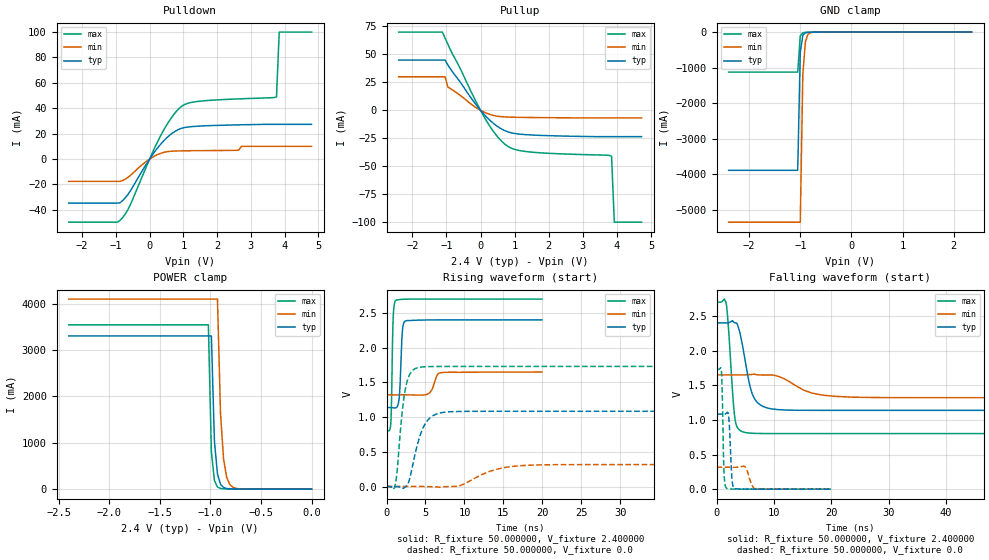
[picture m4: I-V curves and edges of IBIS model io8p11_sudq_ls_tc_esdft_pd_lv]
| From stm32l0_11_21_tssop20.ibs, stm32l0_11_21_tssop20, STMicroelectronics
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|   Model io8p11_sudq_ls_tc_esdft_pd_lv
[Model]  io8p11_sudq_ls_tc_esdft_pd_lv
Model_type I/O
Polarity   Non-Inverting
Enable   Active-Low
Vinl =   0.720000V
Vinh =   1.680000V
Vmeas =  1.200000V
Cref =   50.000000pF
Rref =   100.000000M
Vref =   0.0V
C_comp   2.242700pF   2.201100pF   2.288600pF
[Temperature Range]   25.000000   0.105000k   -40.000000
[Pullup Reference]   2.400000V   1.650000V   2.700000V
[Pulldown Reference]   0.0V   0.0V   0.0V
[POWER Clamp Reference]   2.400000V   1.650000V   2.700000V
[GND Clamp Reference]   0.0V   0.0V   0.0V
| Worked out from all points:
|   slope of the pulldown table from 0 to 0.36 V, typ, clamps not added: 28.4 ohm
|   slope of the pullup table from 0 to 0.36 V, typ, clamps not added: 32.2 ohm
|   GND clamp passes 1 mA (typ) near -0.64 V on its own axis
|   POWER clamp passes 1 mA (typ) near -0.63 V on its own axis
|   rising waveform, R_fixture 50.000000, V_fixture 2.400000: 20-80 % time 282ps typ, 638ps min, 189ps max; typ from 1.14 V to 2.4 V
|   rising waveform, R_fixture 50.000000, V_fixture 0.0: 20-80 % time 1.6ns typ, 3.9ns min, 928ps max; typ from 0 V to 1.08 V
|   falling waveform, R_fixture 50.000000, V_fixture 2.400000: 20-80 % time 1.8ns typ, 4.73ns min, 909ps max; typ from 2.4 V to 1.14 V
|   falling waveform, R_fixture 50.000000, V_fixture 0.0: 20-80 % time 358ps typ, 768ps min, 265ps max; typ from 1.08 V to 0 V
[Pulldown]
|Voltage   I(typ)   I(min)   I(max)
-2.4V     -34.71mA   -17.61mA   -49.77mA
-880mV    -34.55mA   -17.61mA   -48.41mA
-560mV    -24.66mA   -12.69mA   -35.31mA
240mV     8.893mA    3.542mA    13.9mA
560mV     17.98mA    5.931mA    29.16mA
880mV     23.58mA    6.389mA    40.03mA
1.44V     25.89mA    6.593mA    45.41mA
2.64V     26.92mA    7mA        47.38mA
2.72V     26.96mA    10mA       47.46mA
3.76V     27.3mA     10mA       49mA
3.84V     27.3mA     10mA       100mA
4.8V      27.3mA     10mA       100mA
[Pullup]
|Voltage   I(typ)   I(min)   I(max)
-2.4V     45mA       30mA       70mA
-1.12V    45mA       30mA       70mA
-1.04V    45mA       30mA       64.7mA
-960mV    40.7mA     21mA       59.3mA
80mV      -2.838mA   -1.261mA   -4.478mA
480mV     -14.04mA   -5.167mA   -22.91mA
800mV     -19.21mA   -5.978mA   -32.18mA
1.04V     -20.85mA   -6.184mA   -35.23mA
1.44V     -21.93mA   -6.373mA   -37.19mA
3.84V     -23.5mA    -6.7mA     -41mA
3.92V     -23.5mA    -6.7mA     -100mA
4.72V     -23.5mA    -6.7mA     -100mA
[GND_clamp]
|Voltage   I(typ)   I(min)   I(max)
-2.4V     -3.892A    -5.353A    -1.127A
-1.05V    -3.892A    -5.353A    -1.127A
-1V       -568.8mA   -5.353A    -105.4mA
-950mV    -88.96mA   -1.19A     -18.04mA
-900mV    -18.16mA   -269.2mA   -8.968mA
-850mV    -6.712mA   -63.46mA   -6.577mA
-800mV    -4.026mA   -16.62mA   -4.866mA
-650mV    -1.055mA   -1.234mA   -1.154mA
2.35V     53.38uA    50.3uA     37.53uA
[POWER_clamp]
|Voltage   I(typ)   I(min)   I(max)
-2.4V     3.303A     4.097A     3.542A
-1.02V    3.303A     4.097A     3.542A
-990mV    3.303A     4.097A     802.4mA
-960mV    1.032A     4.097A     186.5mA
-930mV    325.2mA    4.097A     47.59mA
-900mV    104.8mA    1.637A     15.78mA
-870mV    35.83mA    655.7mA    8.015mA
-840mV    13.93mA    263.9mA    5.668mA
-810mV    6.712mA    107.2mA    4.56mA
-780mV    4.088mA    44.39mA    3.763mA
-690mV    1.741mA    4.361mA    1.91mA
0V        0A         0A         0A
[Ramp]
| variable   typ   min   max
dV/dt_r  0.65004/1.59528n   0.18967/3.89323n   1.03746/0.92560n
dV/dt_f  0.75702/1.80144n   0.19728/4.72445n   1.13766/0.90706n
R_load = 50.000000
[Rising Waveform]
R_fixture= 50.000000
V_fixture= 2.400000
V_fixture_min= 1.650000
V_fixture_max= 2.700000
|time   V(typ)   V(min)   V(max)
0s        1.137V     1.32V      802.2mV
560.6ps   1.137V     1.32V      929mV
840.8ps   1.133V     1.32V      2.392V
1.201ns   1.133V     1.32V      2.682V
1.602ns   1.254V     1.32V      2.692V
2.042ns   2.246V     1.32V      2.696V
2.442ns   2.385V     1.32V      2.697V
5.405ns   2.398V     1.34V      2.699V
7.047ns   2.399V     1.64V      2.699V
19.94ns   2.399V     1.649V     2.699V
[Rising Waveform]
R_fixture= 50.000000
V_fixture= 0.0
V_fixture_min= 0.0
V_fixture_max= 0.0
|time   V(typ)   V(min)   V(max)
0s        1.003uV    6.542uV    233.6uV
1.126ns   -47.93uV   1.825uV    29.53mV
2.002ns   -17.57mV   -5.005uV   1.066V
2.377ns   -9.593mV   13.27uV    1.38V
3.003ns   125.8mV    75.34uV    1.622V
4.004ns   621.6mV    83.25uV    1.711V
5.506ns   981mV      -1.71mV    1.727V
8.258ns   1.078V     -331.5uV   1.729V
17.14ns   1.083V     299.9mV    1.729V
62.31ns   1.083V     316.1mV    1.729V
[Falling Waveform]
R_fixture= 50.000000
V_fixture= 2.400000
V_fixture_min= 1.650000
V_fixture_max= 2.700000
|time   V(typ)   V(min)   V(max)
0s        2.399V     1.649V     2.699V
1.627ns   2.399V     1.649V     2.704V
2.002ns   2.4V       1.649V     2.418V
3.128ns   2.403V     1.649V     1.07V
3.504ns   2.397V     1.649V     911.9mV
4.505ns   2.084V     1.648V     829.6mV
6.381ns   1.344V     1.658V     806.1mV
9.635ns   1.158V     1.647V     802.5mV
20.9ns    1.137V     1.338V     802.2mV
62.31ns   1.137V     1.32V      802.2mV
[Falling Waveform]
R_fixture= 50.000000
V_fixture= 0.0
V_fixture_min= 0.0
V_fixture_max= 0.0
|time   V(typ)   V(min)   V(max)
0s        1.083V     316.1mV    1.729V
840.8ps   1.083V     316.1mV    1.711V
1.001ns   1.083V     316.1mV    1.365V
1.281ns   1.083V     316.1mV    290.7mV
1.722ns   1.097V     316.1mV    16.64mV
2.122ns   1.046V     316.1mV    3.571mV
2.683ns   151.8mV    315.9mV    1.944mV
3.123ns   11.17mV    315.7mV    1.456mV
6.727ns   577.6uV    7.144mV    275.5uV
19.94ns   1.003uV    6.542uV    233.6uV
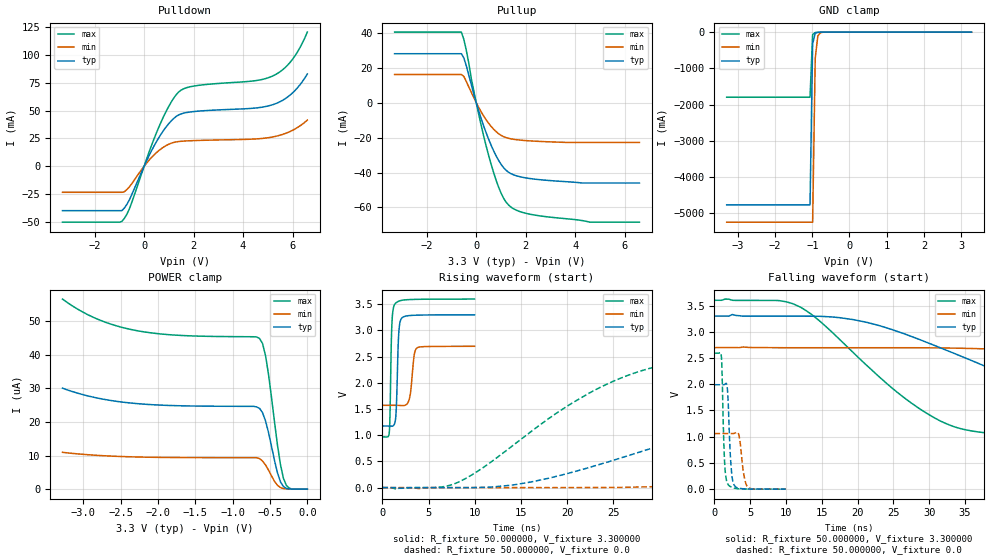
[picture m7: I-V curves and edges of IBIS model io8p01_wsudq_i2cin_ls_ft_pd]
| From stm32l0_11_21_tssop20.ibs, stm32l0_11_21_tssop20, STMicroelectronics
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|   Model io8p01_wsudq_i2cin_ls_ft_pd
[Model]  io8p01_wsudq_i2cin_ls_ft_pd
Model_type I/O
Polarity   Non-Inverting
Enable   Active-Low
Vinl =   0.990000V
Vinh =   2.310000V
Vmeas =  1.650000V
Cref =   50.000000pF
Rref =   100.000000M
Vref =   0.0V
C_comp   3.020400pF   2.988200pF   3.054500pF
[Temperature Range]   25.000000   0.125000k   -40.000000
[Pullup Reference]   3.300000V   2.700000V   3.600000V
[Pulldown Reference]   0.0V   0.0V   0.0V
[POWER Clamp Reference]   3.300000V   2.700000V   3.600000V
[GND Clamp Reference]   0.0V   0.0V   0.0V
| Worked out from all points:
|   slope of the pulldown table from 0 to 0.495 V, typ, clamps not added: 22.6 ohm
|   slope of the pullup table from 0 to 0.495 V, typ, clamps not added: 23.9 ohm
|   GND clamp passes 1 mA (typ) near -0.64 V on its own axis
|   rising waveform, R_fixture 50.000000, V_fixture 3.300000: 20-80 % time 222ps typ, 368ps min, 182ps max; typ from 1.18 V to 3.3 V
|   rising waveform, R_fixture 50.000000, V_fixture 0.0: 20-80 % time 27.1ns typ, 59.4ns min, 13.6ns max; typ from 0 V to 1.99 V
|   falling waveform, R_fixture 50.000000, V_fixture 3.300000: 20-80 % time 24.2ns typ, 53.5ns min, 13.3ns max; typ from 3.3 V to 1.18 V
|   falling waveform, R_fixture 50.000000, V_fixture 0.0: 20-80 % time 406ps typ, 571ps min, 327ps max; typ from 1.99 V to 0 V
[Pulldown]
|Voltage   I(typ)   I(min)   I(max)
-3.3V     -39.83mA   -23.37mA   -50.2mA
-900mV    -39.83mA   -23.37mA   -49.53mA
-600mV    -30.28mA   -18.59mA   -38.45mA
500mV     22.11mA    12.28mA    30.1mA
1V        38.33mA    19.81mA    53.88mA
1.4V      46.1mA     22.18mA    66.72mA
2V        49.07mA    23.02mA    71.93mA
4.4V      52.05mA    24.38mA    76.53mA
5.2V      55.25mA    26.3mA     81.02mA
5.6V      59.18mA    28.57mA    86.57mA
6V        65.79mA    32.24mA    95.97mA
6.6V      82.83mA    41.41mA    120.4mA
[Pullup]
|Voltage   I(typ)   I(min)   I(max)
-3.3V     27.97mA    16.08mA    40.33mA
-600mV    27.97mA    16.08mA    40.33mA
-400mV    21.07mA    12.09mA    29.9mA
-200mV    10.4mA     5.948mA    13.84mA
200mV     -9.115mA   -5.294mA   -12.98mA
600mV     -24.29mA   -13.56mA   -35.12mA
1V        -35.2mA    -18.69mA   -51.62mA
1.2V      -38.62mA   -19.99mA   -56.79mA
1.4V      -40.6mA    -20.72mA   -59.71mA
2.2V      -43.48mA   -21.92mA   -63.91mA
4.6V      -46.01mA   -22.8mA    -68.41mA
6.6V      -46.01mA   -22.8mA    -68.41mA
[GND_clamp]
|Voltage   I(typ)   I(min)   I(max)
-3.3V     -4.766A    -5.244A    -1.797A
-1.06V    -4.766A    -5.244A    -1.797A
-990mV    -326.6mA   -5.244A    -67.91mA
-920mV    -28.93mA   -722.1mA   -10.97mA
-850mV    -6.625mA   -104.2mA   -6.541mA
-780mV    -3.477mA   -17.29mA   -4.218mA
-500mV    -68.5uA    -183uA     -41.48uA
3.28V     73.94uA    88.61uA    51.47uA
[POWER_clamp]
|Voltage   I(typ)   I(min)   I(max)
-3.28V    30.07uA    10.97uA    56.59uA
-2.84V    27.25uA    10.1uA     50.89uA
-2.32V    25.55uA    9.602uA    47.34uA
-640mV    24.06uA    9.099uA    44.84uA
-600mV    22.76uA    8.364uA    43.37uA
-560mV    20.32uA    7.211uA    39.74uA
-520mV    16.86uA    5.675uA    34.14uA
-400mV    4.841uA    1.145uA    13.1uA
-360mV    2.184uA    477.2nA    7.288uA
-320mV    772.4nA    180.3nA    3.213uA
-240mV    60.03nA    0A         295.3nA
0V        0A         0A         0A
[Ramp]
| variable   typ   min   max
dV/dt_r  1.19406/27.03659n   0.63468/59.45171n   1.55520/13.56326n
dV/dt_f  1.27386/24.21250n   0.67098/53.43684n   1.57834/13.29695n
R_load = 50.000000
[Rising Waveform]
R_fixture= 50.000000
V_fixture= 3.300000
V_fixture_min= 2.700000
V_fixture_max= 3.600000
|time   V(typ)   V(min)   V(max)
0s        1.176V     1.571V     968.8mV
740.7ps   1.175V     1.571V     1.037V
1.021ns   1.172V     1.571V     3.074V
1.361ns   1.242V     1.571V     3.506V
1.522ns   1.566V     1.571V     3.534V
1.782ns   2.966V     1.57V      3.559V
2.102ns   3.236V     1.566V     3.576V
2.923ns   3.284V     1.695V     3.589V
3.764ns   3.292V     2.669V     3.594V
9.97ns    3.299V     2.698V     3.599V
[Rising Waveform]
R_fixture= 50.000000
V_fixture= 0.0
V_fixture_min= 0.0
V_fixture_max= 0.0
|time   V(typ)   V(min)   V(max)
0s        -400.3nV   -2.239uV   -178.1nV
8.008ns   -463.6uV   -171.6uV   87.16mV
16.02ns   105.6mV    -142.9uV   1.059V
25.03ns   523.2mV    3.148mV    2.033V
31.03ns   853.3mV    24.34mV    2.365V
39.04ns   1.236V     73.7mV     2.521V
57.56ns   1.754V     279.1mV    2.584V
82.08ns   1.946V     591.6mV    2.591V
137.6ns   1.989V     964.2mV    2.592V
249.2ns   1.99V      1.06V      2.592V
[Falling Waveform]
R_fixture= 50.000000
V_fixture= 3.300000
V_fixture_min= 2.700000
V_fixture_max= 3.600000
|time   V(typ)   V(min)   V(max)
0s        3.299V     2.698V     3.599V
12.01ns   3.296V     2.695V     3.469V
19.52ns   3.229V     2.695V     2.587V
28.53ns   2.859V     2.695V     1.545V
33.53ns   2.586V     2.688V     1.189V
39.04ns   2.274V     2.666V     1.06V
54.55ns   1.528V     2.539V     989.5mV
72.07ns   1.282V     2.306V     974.7mV
125.6ns   1.186V     1.728V     969mV
249.2ns   1.176V     1.571V     968.8mV
[Falling Waveform]
R_fixture= 50.000000
V_fixture= 0.0
V_fixture_min= 0.0
V_fixture_max= 0.0
|time   V(typ)   V(min)   V(max)
0s        1.99V      1.06V      2.592V
961ps     1.99V      1.06V      2.54V
1.401ns   1.994V     1.06V      566.1mV
1.842ns   1.854V     1.06V      103.7mV
2.302ns   475.2mV    1.06V      44.62mV
2.763ns   76.01mV    1.064V     20.65mV
3.423ns   17.84mV    1.026V     6.926mV
4.084ns   6.848mV    294.7mV    3.919mV
4.705ns   3.509mV    32.71mV    2.658mV
9.97ns    -400.3nV   -2.239uV   -178.1nV
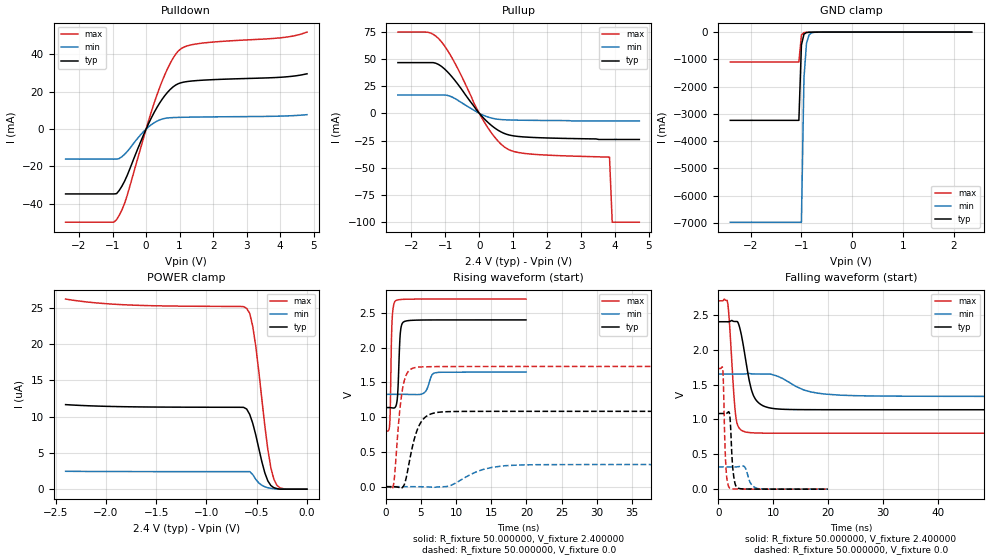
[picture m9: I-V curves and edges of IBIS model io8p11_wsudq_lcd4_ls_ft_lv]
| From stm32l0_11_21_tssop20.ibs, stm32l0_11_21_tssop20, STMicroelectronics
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|   Model io8p11_wsudq_lcd4_ls_ft_lv
[Model]  io8p11_wsudq_lcd4_ls_ft_lv
Model_type I/O
Polarity   Non-Inverting
Enable   Active-Low
Vinl =   0.720000V
Vinh =   1.680000V
Vmeas =  1.200000V
Cref =   50.000000pF
Rref =   100.000000M
Vref =   0.0V
C_comp   3.191400pF   3.178800pF   3.206700pF
[Temperature Range]   25.000000   0.125000k   -40.000000
[Pullup Reference]   2.400000V   1.650000V   2.700000V
[Pulldown Reference]   0.0V   0.0V   0.0V
[POWER Clamp Reference]   2.400000V   1.650000V   2.700000V
[GND Clamp Reference]   0.0V   0.0V   0.0V
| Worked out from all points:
|   slope of the pulldown table from 0 to 0.36 V, typ, clamps not added: 28.5 ohm
|   slope of the pullup table from 0 to 0.36 V, typ, clamps not added: 32.2 ohm
|   GND clamp passes 1 mA (typ) near -0.64 V on its own axis
|   rising waveform, R_fixture 50.000000, V_fixture 2.400000: 20-80 % time 299ps typ, 669ps min, 215ps max; typ from 1.14 V to 2.4 V
|   rising waveform, R_fixture 50.000000, V_fixture 0.0: 20-80 % time 1.6ns typ, 4ns min, 945ps max; typ from 0 V to 1.08 V
|   falling waveform, R_fixture 50.000000, V_fixture 2.400000: 20-80 % time 1.82ns typ, 5.2ns min, 922ps max; typ from 2.4 V to 1.14 V
|   falling waveform, R_fixture 50.000000, V_fixture 0.0: 20-80 % time 498ps typ, 916ps min, 395ps max; typ from 1.08 V to 0 V
[Pulldown]
|Voltage   I(typ)   I(min)   I(max)
-2.4V     -34.7mA    -16.06mA   -49.82mA
-960mV    -34.7mA    -16.06mA   -49.82mA
-880mV    -34.55mA   -16.06mA   -48.46mA
-720mV    -30.52mA   -14.74mA   -43.28mA
-560mV    -24.65mA   -11.94mA   -35.33mA
0V        326fA      0A         20fA
400mV     13.84mA    4.882mA    22.03mA
720mV     21.25mA    6.107mA    35.26mA
1.04V     24.82mA    6.324mA    43.03mA
1.6V      26.11mA    6.486mA    45.88mA
4V        27.76mA    6.965mA    48.87mA
4.8V      29.64mA    7.736mA    51.96mA
[Pullup]
|Voltage   I(typ)   I(min)   I(max)
-2.4V     46.57mA    16.84mA    74.62mA
-1.52V    46.57mA    16.84mA    74.5mA
-1.2V     44.83mA    16.84mA    68.61mA
-720mV    30.24mA    13.64mA    46.11mA
-160mV    6.586mA    2.887mA    9.467mA
160mV     -5.477mA   -2.317mA   -8.695mA
480mV     -14.04mA   -5.139mA   -22.91mA
800mV     -19.2mA    -6.004mA   -32.18mA
1.52V     -22.07mA   -6.444mA   -37.42mA
3.84V     -24mA      -7mA       -40.2mA
3.92V     -24mA      -7mA       -100mA
4.72V     -24mA      -7mA       -100mA
[GND_clamp]
|Voltage   I(typ)   I(min)   I(max)
-2.4V     -3.238A    -6.975A    -1.101A
-1.05V    -3.238A    -6.975A    -1.101A
-1V       -476.5mA   -6.975A    -104.7mA
-950mV    -76.68mA   -1.683A    -18.74mA
-900mV    -16.85mA   -412.3mA   -9.358mA
-850mV    -6.706mA   -104.1mA   -6.778mA
-800mV    -4.108mA   -28.08mA   -4.995mA
-600mV    -527.6uA   -834.9uA   -509uA
2.35V     0A         0A         0A
[POWER_clamp]
|Voltage   I(typ)   I(min)   I(max)
-2.4V     11.64uA    2.461uA    26.18uA
-1.86V    11.37uA    2.426uA    25.43uA
-600mV    11.04uA    2.416uA    24.9uA
-570mV    10.3uA     2.416uA    24.21uA
-540mV    9.097uA    2.018uA    22.48uA
-510mV    7.497uA    1.363uA    19.73uA
-450mV    3.846uA    541.7nA    12.52uA
-390mV    1.155uA    198.9nA    5.528uA
-360mV    508.6nA    120.8nA    2.997uA
-330mV    204.7nA    73.91nA    1.375uA
-270mV    0A         0A         195.3nA
0V        0A         0A         0A
[Ramp]
| variable   typ   min   max
dV/dt_r  0.65070/1.59957n   0.19118/3.99685n   1.03800/0.94111n
dV/dt_f  0.75690/1.81570n   0.18906/5.18158n   1.13815/0.91994n
R_load = 50.000000
[Rising Waveform]
R_fixture= 50.000000
V_fixture= 2.400000
V_fixture_min= 1.650000
V_fixture_max= 2.700000
|time   V(typ)   V(min)   V(max)
0s        1.139V     1.329V     802mV
560.6ps   1.138V     1.329V     917.8mV
880.9ps   1.134V     1.329V     2.383V
1.361ns   1.148V     1.329V     2.673V
1.682ns   1.335V     1.329V     2.688V
2.082ns   2.236V     1.329V     2.693V
2.523ns   2.371V     1.329V     2.696V
5.365ns   2.399V     1.345V     2.7V
7.167ns   2.4V       1.641V     2.7V
19.94ns   2.4V       1.65V      2.7V
[Rising Waveform]
R_fixture= 50.000000
V_fixture= 0.0
V_fixture_min= 0.0
V_fixture_max= 0.0
|time   V(typ)   V(min)   V(max)
0s        -2.603uV   4.603uV    224.3uV
1.001ns   110.8uV    1.245uV    -13.12mV
2.002ns   -17.16mV   -4.372uV   1.122V
2.377ns   -8.273mV   10.56uV    1.41V
3.003ns   180.5mV    76.48uV    1.629V
4.004ns   669.5mV    81.83uV    1.71V
5.38ns    978.9mV    -1.58mV    1.725V
7.883ns   1.075V     -729.4uV   1.729V
17.02ns   1.084V     302.1mV    1.73V
62.31ns   1.085V     318.6mV    1.73V
[Falling Waveform]
R_fixture= 50.000000
V_fixture= 2.400000
V_fixture_min= 1.650000
V_fixture_max= 2.700000
|time   V(typ)   V(min)   V(max)
0s        2.4V       1.65V      2.7V
1.752ns   2.4V       1.65V      2.657V
3.128ns   2.404V     1.65V      1.093V
3.754ns   2.357V     1.65V      882.4mV
4.63ns    2.031V     1.651V     828.6mV
5.631ns   1.565V     1.658V     811.7mV
6.381ns   1.348V     1.652V     807.1mV
9.51ns    1.162V     1.649V     802.7mV
19.52ns   1.139V     1.363V     802.1mV
62.31ns   1.139V     1.329V     802mV
[Falling Waveform]
R_fixture= 50.000000
V_fixture= 0.0
V_fixture_min= 0.0
V_fixture_max= 0.0
|time   V(typ)   V(min)   V(max)
0s        1.085V     318.6mV    1.73V
840.8ps   1.085V     318.6mV    1.709V
1.201ns   1.084V     318.6mV    700.3mV
1.401ns   1.084V     318.6mV    327.8mV
2.042ns   1.089V     318.6mV    18.08mV
2.683ns   278.4mV    318.3mV    4.22mV
3.403ns   26.51mV    319.9mV    2.353mV
4.765ns   2.801mV    322.4mV    1.085mV
7.207ns   783uV      7.885mV    461.7uV
19.94ns   -2.603uV   4.603uV    224.3uV
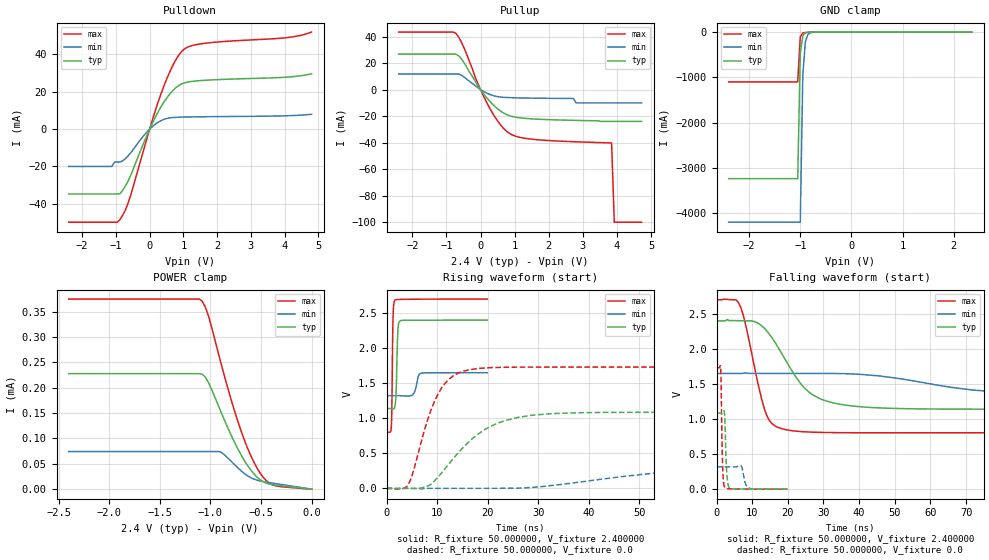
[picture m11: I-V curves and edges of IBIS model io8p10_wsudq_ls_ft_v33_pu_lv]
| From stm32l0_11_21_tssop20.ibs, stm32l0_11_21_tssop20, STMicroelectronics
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|   Model io8p10_wsudq_ls_ft_v33_pu_lv
[Model]  io8p10_wsudq_ls_ft_v33_pu_lv
Model_type I/O
Polarity   Non-Inverting
Enable   Active-Low
Vinl =   0.720000V
Vinh =   1.680000V
Vmeas =  1.200000V
Cref =   50.000000pF
Rref =   100.000000M
Vref =   0.0V
C_comp   2.582000pF   2.574200pF   2.601000pF
[Temperature Range]   25.000000   0.105000k   -40.000000
[Pullup Reference]   2.400000V   1.650000V   2.700000V
[Pulldown Reference]   0.0V   0.0V   0.0V
[POWER Clamp Reference]   2.400000V   1.650000V   2.700000V
[GND Clamp Reference]   0.0V   0.0V   0.0V
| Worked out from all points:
|   slope of the pulldown table from 0 to 0.36 V, typ, clamps not added: 28.5 ohm
|   slope of the pullup table from 0 to 0.36 V, typ, clamps not added: 32.2 ohm
|   GND clamp passes 1 mA (typ) near -0.65 V on its own axis
|   rising waveform, R_fixture 50.000000, V_fixture 2.400000: 20-80 % time 277ps typ, 630ps min, 192ps max; typ from 1.14 V to 2.4 V
|   rising waveform, R_fixture 50.000000, V_fixture 0.0: 20-80 % time 9.32ns typ, 24.5ns min, 4.81ns max; typ from 0.001 V to 1.09 V
|   falling waveform, R_fixture 50.000000, V_fixture 2.400000: 20-80 % time 10.1ns typ, 27.8ns min, 4.95ns max; typ from 2.4 V to 1.14 V
|   falling waveform, R_fixture 50.000000, V_fixture 0.0: 20-80 % time 478ps typ, 843ps min, 381ps max; typ from 1.09 V to 0.001 V
[Pulldown]
|Voltage   I(typ)   I(min)   I(max)
-2.4V     -34.71mA   -20mA      -49.82mA
-1.12V    -34.71mA   -20mA      -49.82mA
-1.04V    -34.71mA   -17.61mA   -49.82mA
-880mV    -34.55mA   -17.61mA   -48.46mA
-560mV    -24.65mA   -12.68mA   -35.33mA
0V        0A         0A         0A
400mV     13.84mA    5.066mA    22.03mA
720mV     21.25mA    6.254mA    35.26mA
1.04V     24.83mA    6.464mA    43.02mA
1.6V      26.11mA    6.627mA    45.88mA
4V        27.76mA    7.125mA    48.88mA
4.8V      29.64mA    7.94mA     51.96mA
[Pullup]
|Voltage   I(typ)   I(min)   I(max)
-2.4V     26.76mA    11.82mA    43.42mA
-720mV    26.76mA    11.82mA    42.41mA
-480mV    20.19mA    9.417mA    31.24mA
-160mV    6.617mA    3.074mA    9.467mA
240mV     -7.917mA   -3.299mA   -12.65mA
560mV     -15.67mA   -5.497mA   -25.76mA
880mV     -19.92mA   -6.062mA   -33.51mA
1.68V     -22.29mA   -6.449mA   -37.81mA
2.8V      -23.2mA    -10mA      -39.35mA
3.84V     -24mA      -10mA      -40.2mA
3.92V     -24mA      -10mA      -100mA
4.72V     -24mA      -10mA      -100mA
[GND_clamp]
|Voltage   I(typ)   I(min)   I(max)
-2.4V     -3.237A    -4.198A    -1.1A
-1.05V    -3.237A    -4.198A    -1.1A
-1V       -475.9mA   -4.198A    -104.3mA
-950mV    -76.36mA   -935.5mA   -18.56mA
-900mV    -16.77mA   -213mA     -9.293mA
-850mV    -6.713mA   -51.08mA   -6.724mA
-800mV    -4.108mA   -13.94mA   -4.924mA
-650mV    -1.048mA   -1.2mA     -1.149mA
2.35V     0A         0A         0A
[POWER_clamp]
|Voltage   I(typ)   I(min)   I(max)
-2.4V     228uA      74.29uA    375.2uA
-1.11V    228uA      74.29uA    375.2uA
-1.08V    227.1uA    74.29uA    370.5uA
-1.02V    210.9uA    74.29uA    342.6uA
-900mV    154.7uA    73.58uA    252.2uA
-810mV    113.1uA    58.15uA    186.8uA
-720mV    76.17uA    40.44uA    128.5uA
-630mV    45.92uA    26.04uA    79.56uA
-540mV    23.97uA    17.88uA    41.93uA
-450mV    12.07uA    14.02uA    17.32uA
-390mV    9.04uA     12.05uA    8.867uA
0V        0A         0A         0A
[Ramp]
| variable   typ   min   max
dV/dt_r  0.65095/9.30996n   0.19037/24.48437n   1.03799/4.79728n
dV/dt_f  0.75618/10.09341n   0.19644/27.76971n   1.13779/4.93497n
R_load = 50.000000
[Rising Waveform]
R_fixture= 50.000000
V_fixture= 2.400000
V_fixture_min= 1.650000
V_fixture_max= 2.700000
|time   V(typ)   V(min)   V(max)
0s        1.14V      1.323V     803.7mV
961ps     1.137V     1.323V     891.4mV
1.281ns   1.132V     1.323V     2.416V
1.642ns   1.168V     1.323V     2.681V
1.882ns   1.348V     1.323V     2.691V
2.242ns   2.247V     1.323V     2.694V
2.603ns   2.384V     1.322V     2.695V
5.285ns   2.399V     1.345V     2.697V
6.767ns   2.399V     1.641V     2.698V
19.94ns   2.4V       1.65V      2.7V
[Rising Waveform]
R_fixture= 50.000000
V_fixture= 0.0
V_fixture_min= 0.0
V_fixture_max= 0.0
|time   V(typ)   V(min)   V(max)
0s        880.8uV    1.332mV    514.1uV
4.505ns   1.741mV    1.443mV    83.37mV
8.509ns   48.16mV    2.278mV    1.06V
11.51ns   276.3mV    2.317mV    1.492V
14.01ns   495.2mV    2.315mV    1.638V
18.02ns   770.3mV    2.34mV     1.71V
26.03ns   1.014V     4.693mV    1.729V
39.54ns   1.082V     104mV      1.73V
85.59ns   1.086V     310.3mV    1.73V
249.2ns   1.086V     318.6mV    1.73V
[Falling Waveform]
R_fixture= 50.000000
V_fixture= 2.400000
V_fixture_min= 1.650000
V_fixture_max= 2.700000
|time   V(typ)   V(min)   V(max)
0s        2.4V       1.65V      2.7V
6.507ns   2.401V     1.65V      2.626V
14.01ns   2.26V      1.65V      1.061V
16.02ns   2.123V     1.65V      916.2mV
20.02ns   1.784V     1.65V      843.1mV
24.52ns   1.45V      1.65V      818.7mV
28.53ns   1.302V     1.65V      810.7mV
43.04ns   1.165V     1.626V     804.2mV
97.1ns    1.14V      1.347V     803.7mV
249.2ns   1.14V      1.323V     803.7mV
[Falling Waveform]
R_fixture= 50.000000
V_fixture= 0.0
V_fixture_min= 0.0
V_fixture_max= 0.0
|time   V(typ)   V(min)   V(max)
0s        1.086V     318.6mV    1.73V
1.161ns   1.086V     318.6mV    1.728V
1.682ns   1.088V     318.6mV    381.3mV
1.922ns   1.107V     318.6mV    123.2mV
2.282ns   1.046V     318.6mV    28.07mV
2.843ns   259.1mV    318.6mV    9.38mV
3.604ns   19.63mV    318.6mV    6.307mV
6.967ns   3.379mV    328.9mV    2.972mV
9.369ns   2.927mV    10.82mV    1.229mV
19.94ns   880.8uV    1.332mV    514.1uV
